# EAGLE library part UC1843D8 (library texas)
PULSE WIDTH MODULATOR

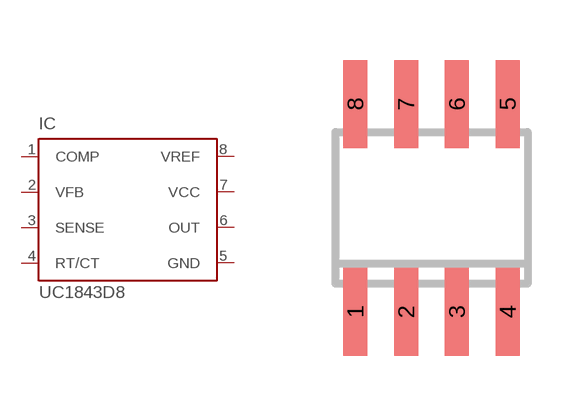
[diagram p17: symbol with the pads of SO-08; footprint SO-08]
Designator prefix IC

## UC1843D8  [SO-08]
1  COMP  pas
2  VFB  in
3  SENSE  in
4  RT/CT  pas
5  GND  pwr
6  OUT  out
7  VCC  pwr
8  VREF  out

## Footprint SO-08 (pad centres in mm)
Small Outline Integrated Circuit
smd 0.6 x 2.2: 1 -1.905,-2.6; 2 -0.635,-2.6; 3 0.635,-2.6; 4 1.905,-2.6; 5 1.905,2.6; 6 0.635,2.6; 7 -0.635,2.6; 8 -1.905,2.6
